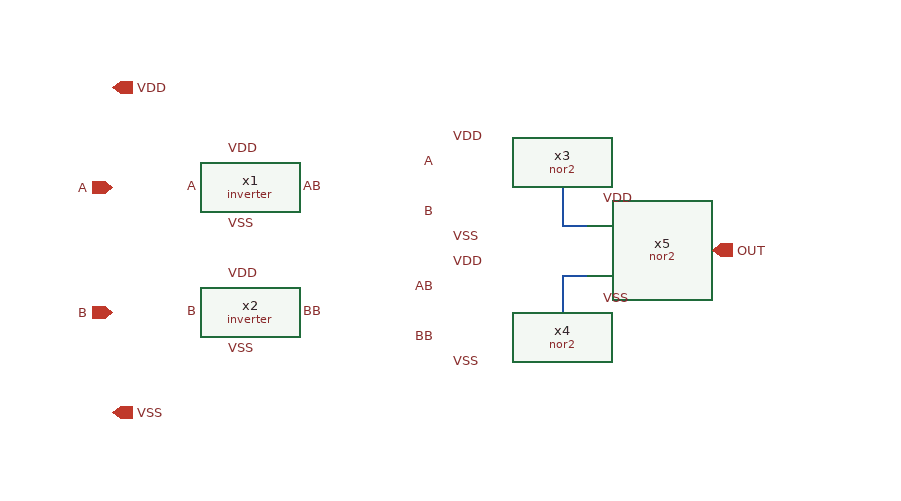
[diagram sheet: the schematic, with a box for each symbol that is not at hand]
v {xschem version=3.4.6 file_version=1.2}
G {}
K {}
V {}
S {}
E {}
N 500 -270 500 -240 {lab=#net1}
N 500 -240 520 -240 {lab=#net1}
N 500 -200 500 -170 {lab=#net2}
N 500 -200 520 -200 {lab=#net2}
C {nor2.sym} 440 -270 0 0 {name=x3}
C {devices/lab_pin.sym} 410 -310 0 1 {name=p6 sig_type=std_logic lab=VDD}
C {devices/lab_pin.sym} 410 -230 0 1 {name=p8 sig_type=std_logic lab=VSS}
C {devices/lab_pin.sym} 400 -290 0 0 {name=p10 sig_type=std_logic lab=A}
C {nor2.sym} 440 -170 0 0 {name=x4}
C {devices/lab_pin.sym} 410 -210 0 1 {name=p13 sig_type=std_logic lab=VDD}
C {devices/lab_pin.sym} 410 -130 0 1 {name=p14 sig_type=std_logic lab=VSS}
C {devices/lab_pin.sym} 400 -190 0 0 {name=p15 sig_type=std_logic lab=AB}
C {devices/lab_pin.sym} 400 -150 0 0 {name=p17 sig_type=std_logic lab=BB}
C {nor2.sym} 560 -220 0 0 {name=x5}
C {devices/lab_pin.sym} 530 -260 0 1 {name=p18 sig_type=std_logic lab=VDD}
C {devices/lab_pin.sym} 530 -180 0 1 {name=p19 sig_type=std_logic lab=VSS}
C {devices/lab_pin.sym} 400 -250 0 0 {name=p4 sig_type=std_logic lab=B}
C {inverter.sym} 250 -270 0 0 {name=x1}
C {devices/lab_pin.sym} 230 -300 0 1 {name=p22 sig_type=std_logic lab=VDD}
C {devices/lab_pin.sym} 230 -240 0 1 {name=p23 sig_type=std_logic lab=VSS}
C {devices/lab_pin.sym} 290 -270 0 1 {name=p25 sig_type=std_logic lab=AB}
C {devices/lab_pin.sym} 210 -270 0 0 {name=p5 sig_type=std_logic lab=A}
C {devices/opin.sym} 620 -220 0 0 {name=p1 lab=OUT}
C {devices/iopin.sym} 140 -350 0 1 {name=p2 lab=VDD
}
C {devices/iopin.sym} 140 -90 0 1 {name=p3 lab=VSS
}
C {devices/ipin.sym} 140 -270 0 0 {name=p33 lab=A}
C {devices/ipin.sym} 140 -170 0 0 {name=p7 lab=B}
C {inverter.sym} 250 -170 0 0 {name=x2}
C {devices/lab_pin.sym} 230 -200 0 1 {name=p9 sig_type=std_logic lab=VDD}
C {devices/lab_pin.sym} 230 -140 0 1 {name=p11 sig_type=std_logic lab=VSS}
C {devices/lab_pin.sym} 290 -170 0 1 {name=p12 sig_type=std_logic lab=BB}
C {devices/lab_pin.sym} 210 -170 0 0 {name=p16 sig_type=std_logic lab=B}
